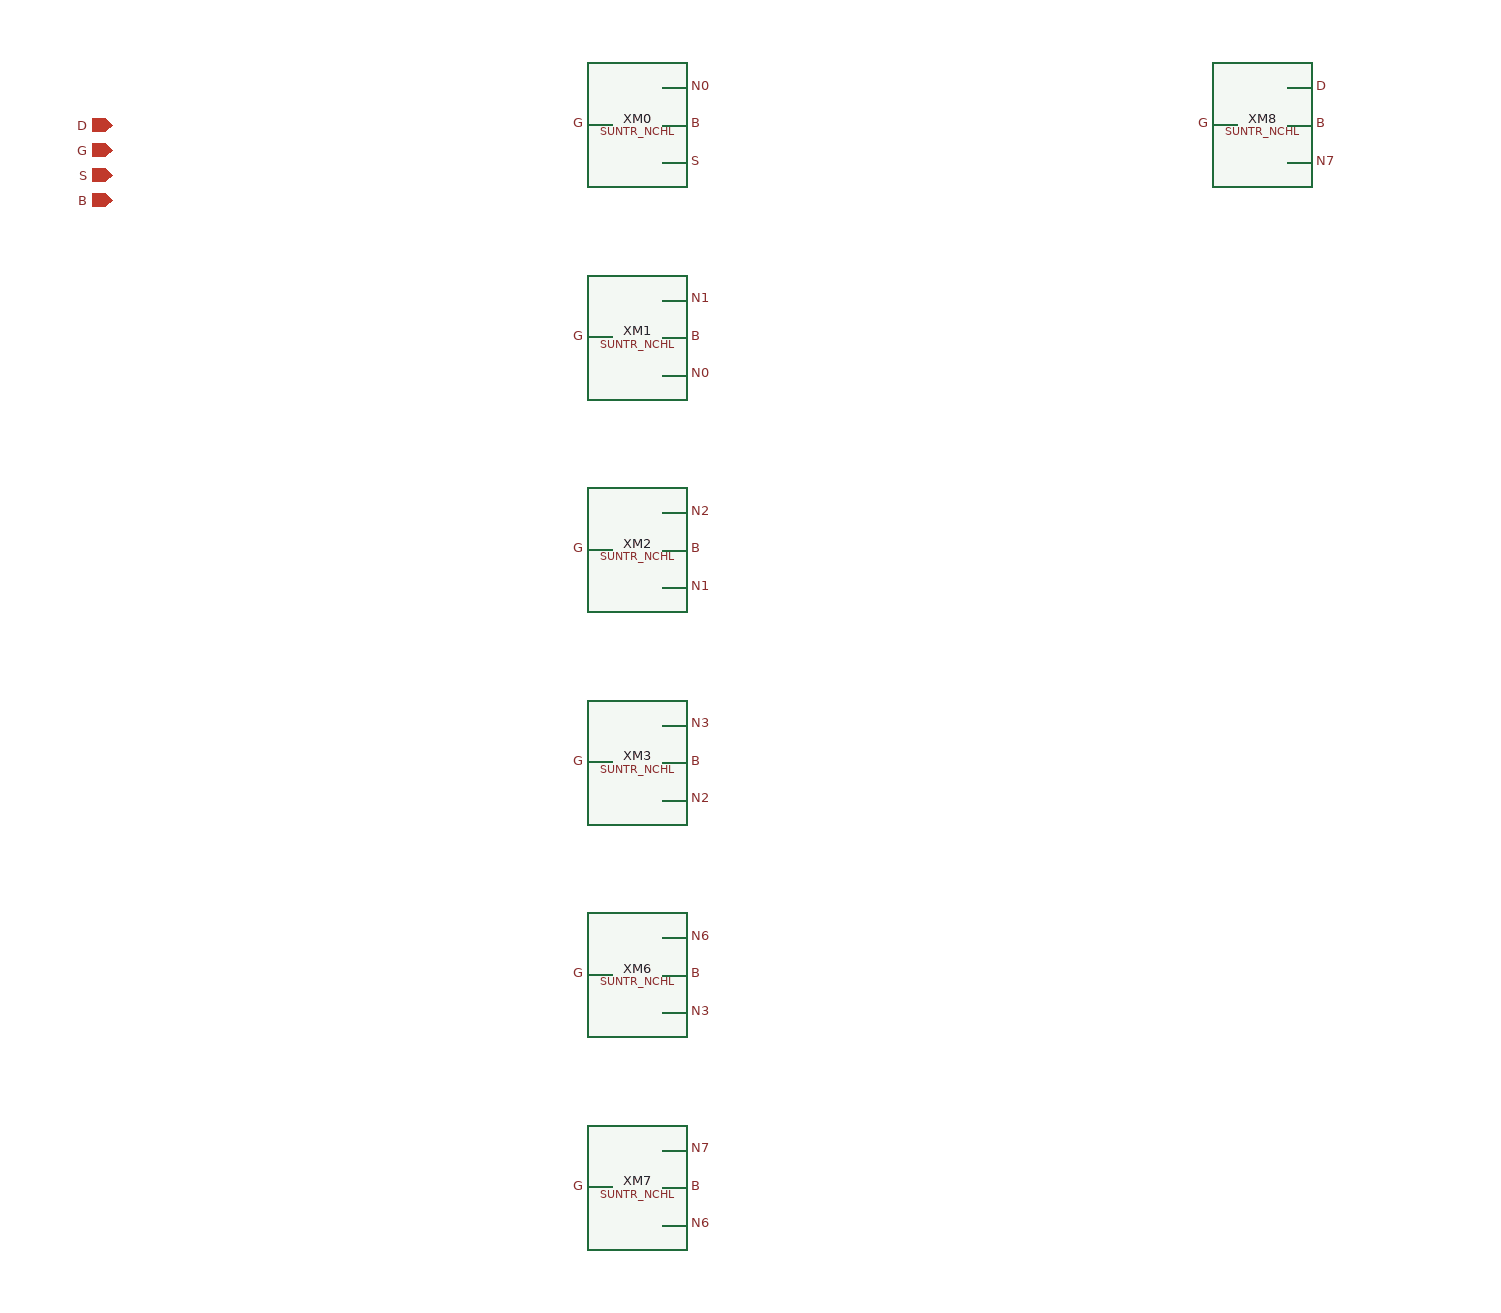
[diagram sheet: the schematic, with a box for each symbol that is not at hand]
v {xschem version=3.0.0 file_version=1.2 }
G {}
K {}
V {}
S {}
E {}
C {devices/iopin.sym} 0 0 0 0{name=p0 lab=D}
C {devices/iopin.sym} 0 20 0 0{name=p1 lab=G}
C {devices/iopin.sym} 0 40 0 0{name=p2 lab=S}
C {devices/iopin.sym} 0 60 0 0{name=p3 lab=B}
C {SUN_TR_SKY130NM/SUNTR_NCHL.sym} 400 0 0 0 {name=XM0}
N 460.0 -30.0 440.0 -30.0{lab=N0}
C {devices/lab_pin.sym} 460.0 -30.0 2 0  {name=l0 sig_type=std_logic lab=N0 }
N 380.0 0.0 400.0 0.0{lab=G}
C {devices/lab_pin.sym} 380.0 0.0 0 0  {name=l1 sig_type=std_logic lab=G }
N 460.0 30.0 440.0 30.0{lab=S}
C {devices/lab_pin.sym} 460.0 30.0 2 0  {name=l2 sig_type=std_logic lab=S }
N 460.0 0.0 440.0 0.0{lab=B}
C {devices/lab_pin.sym} 460.0 0.0 2 0  {name=l3 sig_type=std_logic lab=B }
C {SUN_TR_SKY130NM/SUNTR_NCHL.sym} 400 170.0 0 0 {name=XM1}
N 460.0 140.0 440.0 140.0{lab=N1}
C {devices/lab_pin.sym} 460.0 140.0 2 0  {name=l4 sig_type=std_logic lab=N1 }
N 380.0 170.0 400.0 170.0{lab=G}
C {devices/lab_pin.sym} 380.0 170.0 0 0  {name=l5 sig_type=std_logic lab=G }
N 460.0 200.0 440.0 200.0{lab=N0}
C {devices/lab_pin.sym} 460.0 200.0 2 0  {name=l6 sig_type=std_logic lab=N0 }
N 460.0 170.0 440.0 170.0{lab=B}
C {devices/lab_pin.sym} 460.0 170.0 2 0  {name=l7 sig_type=std_logic lab=B }
C {SUN_TR_SKY130NM/SUNTR_NCHL.sym} 400 340.0 0 0 {name=XM2}
N 460.0 310.0 440.0 310.0{lab=N2}
C {devices/lab_pin.sym} 460.0 310.0 2 0  {name=l8 sig_type=std_logic lab=N2 }
N 380.0 340.0 400.0 340.0{lab=G}
C {devices/lab_pin.sym} 380.0 340.0 0 0  {name=l9 sig_type=std_logic lab=G }
N 460.0 370.0 440.0 370.0{lab=N1}
C {devices/lab_pin.sym} 460.0 370.0 2 0  {name=l10 sig_type=std_logic lab=N1 }
N 460.0 340.0 440.0 340.0{lab=B}
C {devices/lab_pin.sym} 460.0 340.0 2 0  {name=l11 sig_type=std_logic lab=B }
C {SUN_TR_SKY130NM/SUNTR_NCHL.sym} 400 510.0 0 0 {name=XM3}
N 460.0 480.0 440.0 480.0{lab=N3}
C {devices/lab_pin.sym} 460.0 480.0 2 0  {name=l12 sig_type=std_logic lab=N3 }
N 380.0 510.0 400.0 510.0{lab=G}
C {devices/lab_pin.sym} 380.0 510.0 0 0  {name=l13 sig_type=std_logic lab=G }
N 460.0 540.0 440.0 540.0{lab=N2}
C {devices/lab_pin.sym} 460.0 540.0 2 0  {name=l14 sig_type=std_logic lab=N2 }
N 460.0 510.0 440.0 510.0{lab=B}
C {devices/lab_pin.sym} 460.0 510.0 2 0  {name=l15 sig_type=std_logic lab=B }
C {SUN_TR_SKY130NM/SUNTR_NCHL.sym} 400 680.0 0 0 {name=XM6}
N 460.0 650.0 440.0 650.0{lab=N6}
C {devices/lab_pin.sym} 460.0 650.0 2 0  {name=l16 sig_type=std_logic lab=N6 }
N 380.0 680.0 400.0 680.0{lab=G}
C {devices/lab_pin.sym} 380.0 680.0 0 0  {name=l17 sig_type=std_logic lab=G }
N 460.0 710.0 440.0 710.0{lab=N3}
C {devices/lab_pin.sym} 460.0 710.0 2 0  {name=l18 sig_type=std_logic lab=N3 }
N 460.0 680.0 440.0 680.0{lab=B}
C {devices/lab_pin.sym} 460.0 680.0 2 0  {name=l19 sig_type=std_logic lab=B }
C {SUN_TR_SKY130NM/SUNTR_NCHL.sym} 400 850.0 0 0 {name=XM7}
N 460.0 820.0 440.0 820.0{lab=N7}
C {devices/lab_pin.sym} 460.0 820.0 2 0  {name=l20 sig_type=std_logic lab=N7 }
N 380.0 850.0 400.0 850.0{lab=G}
C {devices/lab_pin.sym} 380.0 850.0 0 0  {name=l21 sig_type=std_logic lab=G }
N 460.0 880.0 440.0 880.0{lab=N6}
C {devices/lab_pin.sym} 460.0 880.0 2 0  {name=l22 sig_type=std_logic lab=N6 }
N 460.0 850.0 440.0 850.0{lab=B}
C {devices/lab_pin.sym} 460.0 850.0 2 0  {name=l23 sig_type=std_logic lab=B }
C {SUN_TR_SKY130NM/SUNTR_NCHL.sym} 900 0 0 0 {name=XM8}
N 960.0 -30.0 940.0 -30.0{lab=D}
C {devices/lab_pin.sym} 960.0 -30.0 2 0  {name=l24 sig_type=std_logic lab=D }
N 880.0 0.0 900.0 0.0{lab=G}
C {devices/lab_pin.sym} 880.0 0.0 0 0  {name=l25 sig_type=std_logic lab=G }
N 960.0 30.0 940.0 30.0{lab=N7}
C {devices/lab_pin.sym} 960.0 30.0 2 0  {name=l26 sig_type=std_logic lab=N7 }
N 960.0 0.0 940.0 0.0{lab=B}
C {devices/lab_pin.sym} 960.0 0.0 2 0  {name=l27 sig_type=std_logic lab=B }
